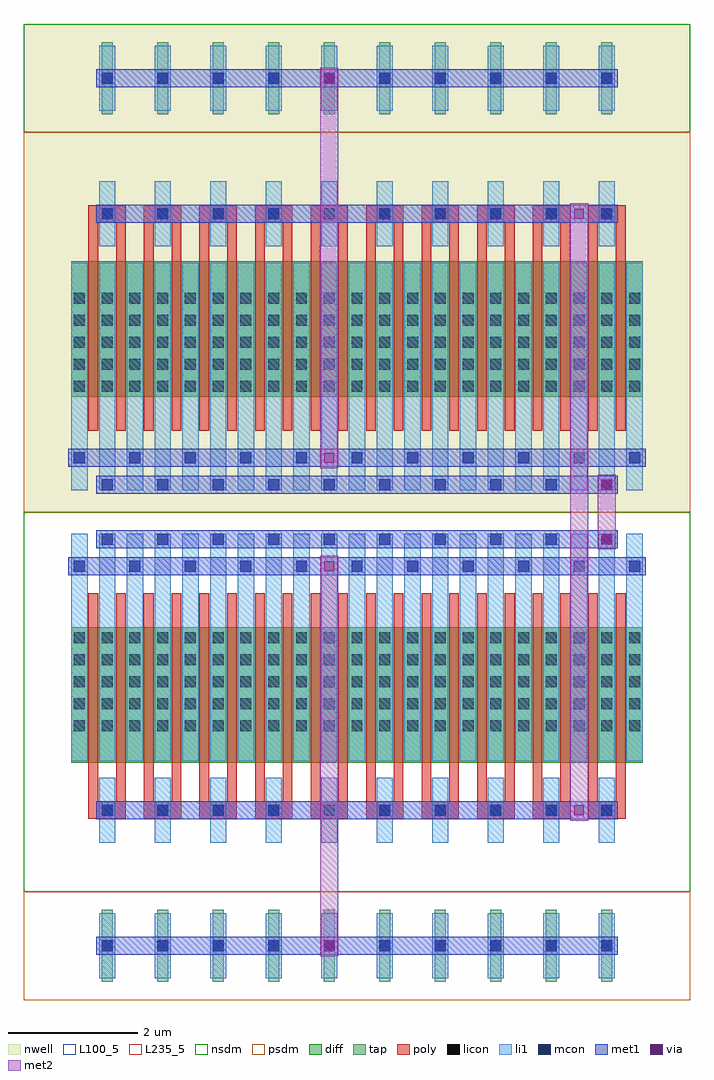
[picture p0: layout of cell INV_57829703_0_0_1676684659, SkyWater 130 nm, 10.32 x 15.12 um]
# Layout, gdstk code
from math import pi, radians
import gdstk
lib = gdstk.Library(unit=1e-6, precision=1e-09)
def R(c, l, rs):  # rectangles x0, y0, x1, y1
    for r in rs: c.add(gdstk.rectangle(r[:2], r[2:], *l))
def A(c, l, x, y, w, h, nx, ny, dx, dy):  # array of equal rectangles
    R(c, l, [(x+i*dx, y+j*dy, x+i*dx+w, y+j*dy+h) for i in range(nx) for j in range(ny)])
def P(c, l, *ps):  # polygons
    for p in ps: c.add(gdstk.Polygon(p, *l))
nwell = (64, 20)
diff = (65, 20)
tap = (65, 44)
poly = (66, 20)
licon = (66, 44)
li1 = (67, 20)
mcon = (67, 44)
met1 = (68, 20)
via = (68, 44)
met2 = (69, 20)
nsdm = (93, 44)
psdm = (94, 20)
L100_5 = (100, 5)
L235_5 = (235, 5)

nmos_s_94162904_x10_y1_1 = lib.new_cell('NMOS_S_94162904_X10_Y1_1676684653_1676684659')
R(nmos_s_94162904_x10_y1_1, diff, [(0.735,1.785,9.585,3.885)])
A(nmos_s_94162904_x10_y1_1, tap, 1.205, 6.16, 0.17, 1.12, 10, 1, 0.86, 0)
A(nmos_s_94162904_x10_y1_1, poly, 1, 1.26, 0.15, 3.36, 20, 1, 0.43, 0)
A(nmos_s_94162904_x10_y1_1, poly, 1, 4.485, 0.58, 0.27, 10, 1, 0.86, 0)
A(nmos_s_94162904_x10_y1_1, licon, 0.775, 1.865, 0.17, 0.17, 3, 5, 0.43, 0.34)
A(nmos_s_94162904_x10_y1_1, licon, 1.635, 1.865, 0.17, 0.17, 3, 5, 0.43, 0.34)
A(nmos_s_94162904_x10_y1_1, licon, 2.495, 1.865, 0.17, 0.17, 3, 5, 0.43, 0.34)
A(nmos_s_94162904_x10_y1_1, licon, 3.355, 1.865, 0.17, 0.17, 3, 5, 0.43, 0.34)
A(nmos_s_94162904_x10_y1_1, licon, 4.215, 1.865, 0.17, 0.17, 3, 5, 0.43, 0.34)
A(nmos_s_94162904_x10_y1_1, licon, 5.075, 1.865, 0.17, 0.17, 3, 5, 0.43, 0.34)
A(nmos_s_94162904_x10_y1_1, licon, 5.935, 1.865, 0.17, 0.17, 3, 5, 0.43, 0.34)
A(nmos_s_94162904_x10_y1_1, licon, 6.795, 1.865, 0.17, 0.17, 3, 5, 0.43, 0.34)
A(nmos_s_94162904_x10_y1_1, licon, 7.655, 1.865, 0.17, 0.17, 3, 5, 0.43, 0.34)
A(nmos_s_94162904_x10_y1_1, licon, 8.515, 1.865, 0.17, 0.17, 3, 5, 0.43, 0.34)
A(nmos_s_94162904_x10_y1_1, licon, 1.205, 4.535, 0.17, 0.17, 10, 2, 0.86, 2.1)
A(nmos_s_94162904_x10_y1_1, li1, 0.735, 0.335, 0.25, 3.53, 21, 1, 0.43, 0)
A(nmos_s_94162904_x10_y1_1, li1, 1.165, 4.115, 0.25, 1.01, 10, 2, 0.86, 2.1)
A(nmos_s_94162904_x10_y1_1, mcon, 1.205, 0.335, 0.17, 0.17, 10, 2, 0.86, 4.2)
A(nmos_s_94162904_x10_y1_1, mcon, 0.775, 0.755, 0.17, 0.17, 11, 1, 0.86, 0)
A(nmos_s_94162904_x10_y1_1, mcon, 1.205, 6.635, 0.17, 0.17, 10, 1, 0.86, 0)
R(nmos_s_94162904_x10_y1_1, met1, [(1.12,0.28,9.2,0.56), (0.69,0.7,9.63,0.98), (1.12,4.48,9.2,4.76), (1.12,6.58,9.2,6.86)])
R(nmos_s_94162904_x10_y1_1, via, [(5.515,0.765,5.665,0.915), (5.515,6.645,5.665,6.795)])
R(nmos_s_94162904_x10_y1_1, met2, [(5.45,0.68,5.73,6.88)])
R(nmos_s_94162904_x10_y1_1, nsdm, [(0,0,10.32,5.88)])
R(nmos_s_94162904_x10_y1_1, psdm, [(0,5.88,10.32,7.56)])
R(nmos_s_94162904_x10_y1_1, L100_5, [(0,0,10.32,7.56)])

pmos_s_75841860_x10_y1_1 = lib.new_cell('PMOS_S_75841860_X10_Y1_1676684654_1676684659')
R(pmos_s_75841860_x10_y1_1, nwell, [(0,0,10.32,7.56)])
R(pmos_s_75841860_x10_y1_1, diff, [(0.735,1.785,9.585,3.885)])
A(pmos_s_75841860_x10_y1_1, tap, 1.205, 6.16, 0.17, 1.12, 10, 1, 0.86, 0)
A(pmos_s_75841860_x10_y1_1, poly, 1, 1.26, 0.15, 3.36, 20, 1, 0.43, 0)
A(pmos_s_75841860_x10_y1_1, poly, 1, 4.485, 0.58, 0.27, 10, 1, 0.86, 0)
A(pmos_s_75841860_x10_y1_1, licon, 0.775, 1.865, 0.17, 0.17, 3, 5, 0.43, 0.34)
A(pmos_s_75841860_x10_y1_1, licon, 1.635, 1.865, 0.17, 0.17, 3, 5, 0.43, 0.34)
A(pmos_s_75841860_x10_y1_1, licon, 2.495, 1.865, 0.17, 0.17, 3, 5, 0.43, 0.34)
A(pmos_s_75841860_x10_y1_1, licon, 3.355, 1.865, 0.17, 0.17, 3, 5, 0.43, 0.34)
A(pmos_s_75841860_x10_y1_1, licon, 4.215, 1.865, 0.17, 0.17, 3, 5, 0.43, 0.34)
A(pmos_s_75841860_x10_y1_1, licon, 5.075, 1.865, 0.17, 0.17, 3, 5, 0.43, 0.34)
A(pmos_s_75841860_x10_y1_1, licon, 5.935, 1.865, 0.17, 0.17, 3, 5, 0.43, 0.34)
A(pmos_s_75841860_x10_y1_1, licon, 6.795, 1.865, 0.17, 0.17, 3, 5, 0.43, 0.34)
A(pmos_s_75841860_x10_y1_1, licon, 7.655, 1.865, 0.17, 0.17, 3, 5, 0.43, 0.34)
A(pmos_s_75841860_x10_y1_1, licon, 8.515, 1.865, 0.17, 0.17, 3, 5, 0.43, 0.34)
A(pmos_s_75841860_x10_y1_1, licon, 1.205, 4.535, 0.17, 0.17, 10, 2, 0.86, 2.1)
A(pmos_s_75841860_x10_y1_1, li1, 0.735, 0.335, 0.25, 3.53, 21, 1, 0.43, 0)
A(pmos_s_75841860_x10_y1_1, li1, 1.165, 4.115, 0.25, 1.01, 10, 2, 0.86, 2.1)
A(pmos_s_75841860_x10_y1_1, mcon, 1.205, 0.335, 0.17, 0.17, 10, 2, 0.86, 4.2)
A(pmos_s_75841860_x10_y1_1, mcon, 0.775, 0.755, 0.17, 0.17, 11, 1, 0.86, 0)
A(pmos_s_75841860_x10_y1_1, mcon, 1.205, 6.635, 0.17, 0.17, 10, 1, 0.86, 0)
R(pmos_s_75841860_x10_y1_1, met1, [(1.12,0.28,9.2,0.56), (0.69,0.7,9.63,0.98), (1.12,4.48,9.2,4.76), (1.12,6.58,9.2,6.86)])
R(pmos_s_75841860_x10_y1_1, via, [(5.515,0.765,5.665,0.915), (5.515,6.645,5.665,6.795)])
R(pmos_s_75841860_x10_y1_1, met2, [(5.45,0.68,5.73,6.88)])
R(pmos_s_75841860_x10_y1_1, nsdm, [(0,5.88,10.32,7.56)])
R(pmos_s_75841860_x10_y1_1, psdm, [(0,0,10.32,5.88)])
R(pmos_s_75841860_x10_y1_1, L100_5, [(0,0,10.32,7.56)])

inv_57829703_0_0_1676684 = lib.new_cell('INV_57829703_0_0_1676684659')
R(inv_57829703_0_0_1676684, met1, [(8.44,2.8,8.76,3.08), (8.44,2.8,8.76,3.08), (8.87,7,9.19,7.28), (8.87,7,9.19,7.28), (8.87,7.84,9.19,8.12), (8.87,7.84,9.19,8.12), (8.44,12.04,8.76,12.32), (8.44,12.04,8.76,12.32)])
P(inv_57829703_0_0_1676684, met1, [(0,0),(0,0),(0,0),(0,0)],
  [(0,0),(0,0),(0,0),(0,0)],
  [(0,0),(0,0),(0,0),(0,0)],
  [(0,0),(0,0),(0,0),(0,0)])
R(inv_57829703_0_0_1676684, via, [(8.525,2.865,8.675,3.015), (8.525,2.865,8.675,3.015), (8.955,7.065,9.105,7.215), (8.955,7.065,9.105,7.215), (8.955,7.905,9.105,8.055), (8.955,7.905,9.105,8.055), (8.525,12.105,8.675,12.255), (8.525,12.105,8.675,12.255)])
R(inv_57829703_0_0_1676684, met2, [(8.46,2.78,8.74,3.1), (8.46,2.78,8.74,3.1), (8.46,2.94,8.74,12.18), (8.89,6.98,9.17,7.3), (8.89,6.98,9.17,7.3), (8.89,7.14,9.17,7.98), (8.89,7.82,9.17,8.14), (8.89,7.82,9.17,8.14), (8.46,12.02,8.74,12.34), (8.46,12.02,8.74,12.34)])
P(inv_57829703_0_0_1676684, met2, [(0,0),(0,0),(0,0),(0,0)],
  [(0,0),(0,0),(0,0),(0,0)])
R(inv_57829703_0_0_1676684, L235_5, [(0,0,10.32,15.12)])
inv_57829703_0_0_1676684.add(gdstk.Reference(nmos_s_94162904_x10_y1_1, (10.32,7.56), rotation=pi))
inv_57829703_0_0_1676684.add(gdstk.Reference(pmos_s_75841860_x10_y1_1, (10.32,7.56), rotation=pi, x_reflection=True))

lib.write_gds('INV_57829703_0_0_1676684659.gds')
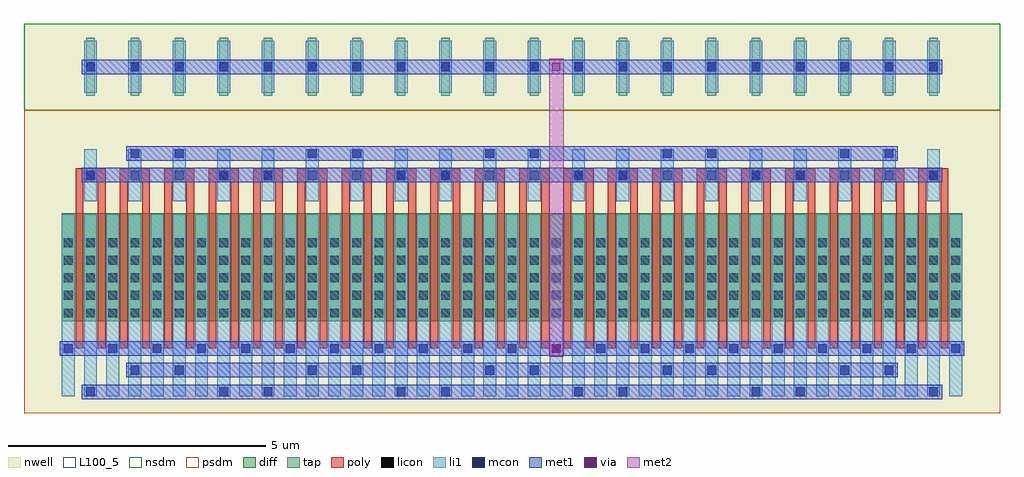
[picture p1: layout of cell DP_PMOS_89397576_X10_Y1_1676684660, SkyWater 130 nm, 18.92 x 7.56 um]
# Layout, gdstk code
import gdstk
lib = gdstk.Library(unit=1e-6, precision=1e-09)
def R(c, l, rs):  # rectangles x0, y0, x1, y1
    for r in rs: c.add(gdstk.rectangle(r[:2], r[2:], *l))
def A(c, l, x, y, w, h, nx, ny, dx, dy):  # array of equal rectangles
    R(c, l, [(x+i*dx, y+j*dy, x+i*dx+w, y+j*dy+h) for i in range(nx) for j in range(ny)])
nwell = (64, 20)
diff = (65, 20)
tap = (65, 44)
poly = (66, 20)
licon = (66, 44)
li1 = (67, 20)
mcon = (67, 44)
met1 = (68, 20)
via = (68, 44)
met2 = (69, 20)
nsdm = (93, 44)
psdm = (94, 20)
L100_5 = (100, 5)

dp_pmos_89397576_x10_y1_ = lib.new_cell('DP_PMOS_89397576_X10_Y1_1676684660')
R(dp_pmos_89397576_x10_y1_, nwell, [(0,0,18.92,7.56)])
R(dp_pmos_89397576_x10_y1_, diff, [(0.735,1.785,18.185,3.885)])
A(dp_pmos_89397576_x10_y1_, tap, 1.205, 6.16, 0.17, 1.12, 20, 1, 0.86, 0)
A(dp_pmos_89397576_x10_y1_, poly, 1, 1.26, 0.15, 3.36, 40, 1, 0.43, 0)
A(dp_pmos_89397576_x10_y1_, poly, 1, 4.485, 0.58, 0.27, 20, 1, 0.86, 0)
A(dp_pmos_89397576_x10_y1_, licon, 0.775, 1.865, 0.17, 0.17, 3, 5, 0.43, 0.34)
A(dp_pmos_89397576_x10_y1_, licon, 1.635, 1.865, 0.17, 0.17, 3, 5, 0.43, 0.34)
A(dp_pmos_89397576_x10_y1_, licon, 2.495, 1.865, 0.17, 0.17, 3, 5, 0.43, 0.34)
A(dp_pmos_89397576_x10_y1_, licon, 3.355, 1.865, 0.17, 0.17, 3, 5, 0.43, 0.34)
A(dp_pmos_89397576_x10_y1_, licon, 4.215, 1.865, 0.17, 0.17, 3, 5, 0.43, 0.34)
A(dp_pmos_89397576_x10_y1_, licon, 5.075, 1.865, 0.17, 0.17, 3, 5, 0.43, 0.34)
A(dp_pmos_89397576_x10_y1_, licon, 5.935, 1.865, 0.17, 0.17, 3, 5, 0.43, 0.34)
A(dp_pmos_89397576_x10_y1_, licon, 6.795, 1.865, 0.17, 0.17, 3, 5, 0.43, 0.34)
A(dp_pmos_89397576_x10_y1_, licon, 7.655, 1.865, 0.17, 0.17, 3, 5, 0.43, 0.34)
A(dp_pmos_89397576_x10_y1_, licon, 8.515, 1.865, 0.17, 0.17, 3, 5, 0.43, 0.34)
A(dp_pmos_89397576_x10_y1_, licon, 9.375, 1.865, 0.17, 0.17, 3, 5, 0.43, 0.34)
A(dp_pmos_89397576_x10_y1_, licon, 10.235, 1.865, 0.17, 0.17, 3, 5, 0.43, 0.34)
A(dp_pmos_89397576_x10_y1_, licon, 11.095, 1.865, 0.17, 0.17, 3, 5, 0.43, 0.34)
A(dp_pmos_89397576_x10_y1_, licon, 11.955, 1.865, 0.17, 0.17, 3, 5, 0.43, 0.34)
A(dp_pmos_89397576_x10_y1_, licon, 12.815, 1.865, 0.17, 0.17, 3, 5, 0.43, 0.34)
A(dp_pmos_89397576_x10_y1_, licon, 13.675, 1.865, 0.17, 0.17, 3, 5, 0.43, 0.34)
A(dp_pmos_89397576_x10_y1_, licon, 14.535, 1.865, 0.17, 0.17, 3, 5, 0.43, 0.34)
A(dp_pmos_89397576_x10_y1_, licon, 15.395, 1.865, 0.17, 0.17, 3, 5, 0.43, 0.34)
A(dp_pmos_89397576_x10_y1_, licon, 16.255, 1.865, 0.17, 0.17, 3, 5, 0.43, 0.34)
A(dp_pmos_89397576_x10_y1_, licon, 17.115, 1.865, 0.17, 0.17, 3, 5, 0.43, 0.34)
A(dp_pmos_89397576_x10_y1_, licon, 1.205, 4.535, 0.17, 0.17, 20, 2, 0.86, 2.1)
A(dp_pmos_89397576_x10_y1_, li1, 0.735, 0.335, 0.25, 3.53, 41, 1, 0.43, 0)
A(dp_pmos_89397576_x10_y1_, li1, 1.165, 4.115, 0.25, 1.01, 20, 2, 0.86, 2.1)
A(dp_pmos_89397576_x10_y1_, mcon, 0.775, 1.175, 0.17, 0.17, 21, 1, 0.86, 0)
A(dp_pmos_89397576_x10_y1_, mcon, 1.205, 6.635, 0.17, 0.17, 20, 1, 0.86, 0)
R(dp_pmos_89397576_x10_y1_, mcon, [(1.205,0.335,1.375,0.505), (3.785,0.335,3.955,0.505), (4.645,0.335,4.815,0.505), (7.225,0.335,7.395,0.505), (8.085,0.335,8.255,0.505), (10.665,0.335,10.835,0.505), (11.525,0.335,11.695,0.505), (14.105,0.335,14.275,0.505), (14.965,0.335,15.135,0.505), (17.545,0.335,17.715,0.505), (2.065,0.755,2.235,0.925), (2.925,0.755,3.095,0.925), (5.505,0.755,5.675,0.925), (6.365,0.755,6.535,0.925), (8.945,0.755,9.115,0.925), (9.805,0.755,9.975,0.925), (12.385,0.755,12.555,0.925), (13.245,0.755,13.415,0.925), (15.825,0.755,15.995,0.925), (16.685,0.755,16.855,0.925), (1.205,4.535,1.375,4.705), (3.785,4.535,3.955,4.705), (4.645,4.535,4.815,4.705), (7.225,4.535,7.395,4.705), (8.085,4.535,8.255,4.705), (10.665,4.535,10.835,4.705), (11.525,4.535,11.695,4.705), (14.105,4.535,14.275,4.705), (14.965,4.535,15.135,4.705), (17.545,4.535,17.715,4.705), (2.065,4.955,2.235,5.125), (2.925,4.955,3.095,5.125), (5.505,4.955,5.675,5.125), (6.365,4.955,6.535,5.125), (8.945,4.955,9.115,5.125), (9.805,4.955,9.975,5.125), (12.385,4.955,12.555,5.125), (13.245,4.955,13.415,5.125), (15.825,4.955,15.995,5.125), (16.685,4.955,16.855,5.125)])
R(dp_pmos_89397576_x10_y1_, met1, [(1.12,0.28,17.8,0.56), (1.98,0.7,16.94,0.98), (0.69,1.12,18.23,1.4), (1.12,4.48,17.8,4.76), (1.98,4.9,16.94,5.18), (1.12,6.58,17.8,6.86)])
R(dp_pmos_89397576_x10_y1_, via, [(10.245,1.185,10.395,1.335), (10.245,6.645,10.395,6.795)])
R(dp_pmos_89397576_x10_y1_, met2, [(10.18,1.1,10.46,6.88)])
R(dp_pmos_89397576_x10_y1_, nsdm, [(0,5.88,18.92,7.56)])
R(dp_pmos_89397576_x10_y1_, psdm, [(0,0,18.92,5.88)])
R(dp_pmos_89397576_x10_y1_, L100_5, [(0,0,18.92,7.56)])

lib.write_gds('DP_PMOS_89397576_X10_Y1_1676684660.gds')
